VERSION 5.8 ;
BUSBITCHARS "[]" ;
DIVIDERCHAR "/" ;
UNITS
    DATABASE MICRONS 2000 ;
END UNITS

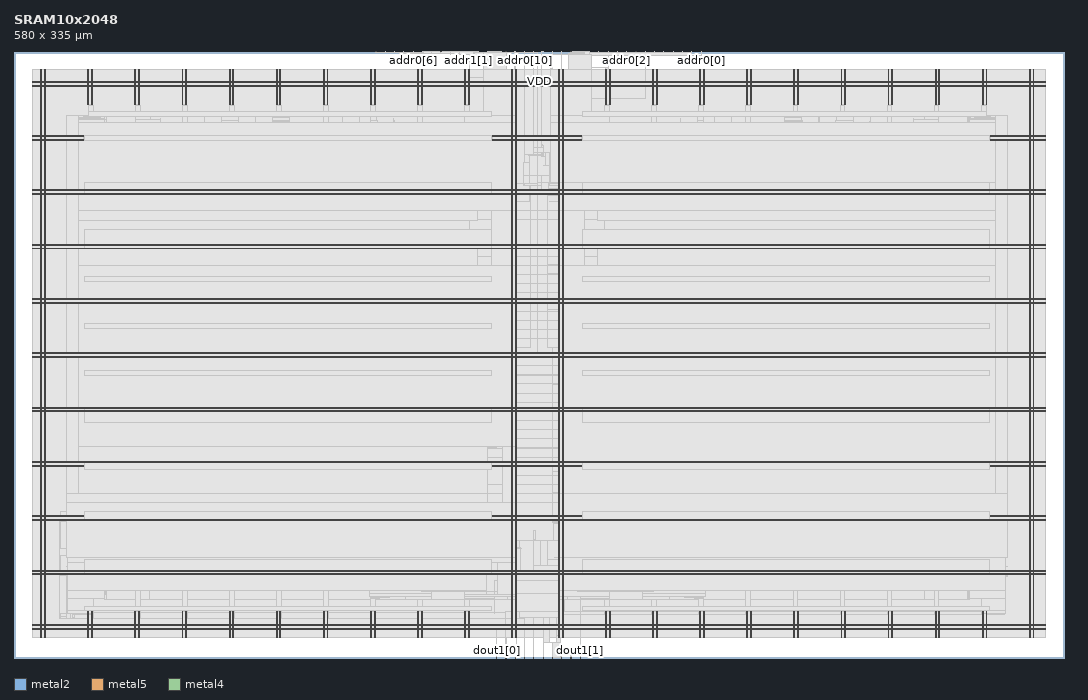
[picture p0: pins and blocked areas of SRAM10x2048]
MACRO SRAM10x2048
  FOREIGN SRAM10x2048 0 0 ;
  CLASS BLOCK ;
  SIZE 580 BY 335 ;
  PIN addr0[0]
    DIRECTION INPUT ;
    USE SIGNAL ;
    PORT
      LAYER metal2 ;
        RECT  379.49 334.93 379.56 335 ;
    END
  END addr0[0]
  PIN addr0[10]
    DIRECTION INPUT ;
    USE SIGNAL ;
    PORT
      LAYER metal2 ;
        RECT  282.02 334.93 282.09 335 ;
    END
  END addr0[10]
  PIN addr0[1]
    DIRECTION INPUT ;
    USE SIGNAL ;
    PORT
      LAYER metal2 ;
        RECT  369.23 334.93 369.3 335 ;
    END
  END addr0[1]
  PIN addr0[2]
    DIRECTION INPUT ;
    USE SIGNAL ;
    PORT
      LAYER metal2 ;
        RECT  338.45 334.93 338.52 335 ;
    END
  END addr0[2]
  PIN addr0[3]
    DIRECTION INPUT ;
    USE SIGNAL ;
    PORT
      LAYER metal2 ;
        RECT  374.36 334.93 374.43 335 ;
    END
  END addr0[3]
  PIN addr0[4]
    DIRECTION INPUT ;
    USE SIGNAL ;
    PORT
      LAYER metal2 ;
        RECT  240.98 334.93 241.05 335 ;
    END
  END addr0[4]
  PIN addr0[5]
    DIRECTION INPUT ;
    USE SIGNAL ;
    PORT
      LAYER metal2 ;
        RECT  302.54 334.93 302.61 335 ;
    END
  END addr0[5]
  PIN addr0[6]
    DIRECTION INPUT ;
    USE SIGNAL ;
    PORT
      LAYER metal2 ;
        RECT  220.46 334.93 220.53 335 ;
    END
  END addr0[6]
  PIN addr0[7]
    DIRECTION INPUT ;
    USE SIGNAL ;
    PORT
      LAYER metal2 ;
        RECT  261.5 334.93 261.57 335 ;
    END
  END addr0[7]
  PIN addr0[8]
    DIRECTION INPUT ;
    USE SIGNAL ;
    PORT
      LAYER metal2 ;
        RECT  317.93 334.93 318 335 ;
    END
  END addr0[8]
  PIN addr0[9]
    DIRECTION INPUT ;
    USE SIGNAL ;
    PORT
      LAYER metal2 ;
        RECT  235.85 334.93 235.92 335 ;
    END
  END addr0[9]
  PIN addr1[0]
    DIRECTION INPUT ;
    USE SIGNAL ;
    PORT
      LAYER metal2 ;
        RECT  328.19 334.93 328.26 335 ;
    END
  END addr1[0]
  PIN addr1[10]
    DIRECTION INPUT ;
    USE SIGNAL ;
    PORT
      LAYER metal2 ;
        RECT  292.28 334.93 292.35 335 ;
    END
  END addr1[10]
  PIN addr1[1]
    DIRECTION INPUT ;
    USE SIGNAL ;
    PORT
      LAYER metal2 ;
        RECT  251.24 334.93 251.31 335 ;
    END
  END addr1[1]
  PIN addr1[2]
    DIRECTION INPUT ;
    USE SIGNAL ;
    PORT
      LAYER metal2 ;
        RECT  271.76 334.93 271.83 335 ;
    END
  END addr1[2]
  PIN addr1[3]
    DIRECTION INPUT ;
    USE SIGNAL ;
    PORT
      LAYER metal2 ;
        RECT  333.32 334.93 333.39 335 ;
    END
  END addr1[3]
  PIN addr1[4]
    DIRECTION INPUT ;
    USE SIGNAL ;
    PORT
      LAYER metal2 ;
        RECT  230.72 334.93 230.79 335 ;
    END
  END addr1[4]
  PIN addr1[5]
    DIRECTION INPUT ;
    USE SIGNAL ;
    PORT
      LAYER metal2 ;
        RECT  256.37 334.93 256.44 335 ;
    END
  END addr1[5]
  PIN addr1[6]
    DIRECTION INPUT ;
    USE SIGNAL ;
    PORT
      LAYER metal2 ;
        RECT  266.63 334.93 266.7 335 ;
    END
  END addr1[6]
  PIN addr1[7]
    DIRECTION INPUT ;
    USE SIGNAL ;
    PORT
      LAYER metal2 ;
        RECT  348.71 334.93 348.78 335 ;
    END
  END addr1[7]
  PIN addr1[8]
    DIRECTION INPUT ;
    USE SIGNAL ;
    PORT
      LAYER metal2 ;
        RECT  323.06 334.93 323.13 335 ;
    END
  END addr1[8]
  PIN addr1[9]
    DIRECTION INPUT ;
    USE SIGNAL ;
    PORT
      LAYER metal2 ;
        RECT  210.2 334.93 210.27 335 ;
    END
  END addr1[9]
  PIN clk0
    DIRECTION INPUT ;
    USE SIGNAL ;
    PORT
      LAYER metal2 ;
        RECT  225.59 334.93 225.66 335 ;
    END
  END clk0
  PIN clk1
    DIRECTION INPUT ;
    USE SIGNAL ;
    PORT
      LAYER metal2 ;
        RECT  358.97 334.93 359.04 335 ;
    END
  END clk1
  PIN csb0
    DIRECTION INPUT ;
    USE SIGNAL ;
    PORT
      LAYER metal2 ;
        RECT  297.41 334.93 297.48 335 ;
    END
  END csb0
  PIN csb1
    DIRECTION INPUT ;
    USE SIGNAL ;
    PORT
      LAYER metal2 ;
        RECT  287.15 334.93 287.22 335 ;
    END
  END csb1
  PIN din0[0]
    DIRECTION INPUT ;
    USE SIGNAL ;
    PORT
      LAYER metal2 ;
        RECT  205.07 334.93 205.14 335 ;
    END
  END din0[0]
  PIN din0[1]
    DIRECTION INPUT ;
    USE SIGNAL ;
    PORT
      LAYER metal2 ;
        RECT  215.33 334.93 215.4 335 ;
    END
  END din0[1]
  PIN din0[2]
    DIRECTION INPUT ;
    USE SIGNAL ;
    PORT
      LAYER metal2 ;
        RECT  312.8 334.93 312.87 335 ;
    END
  END din0[2]
  PIN din0[3]
    DIRECTION INPUT ;
    USE SIGNAL ;
    PORT
      LAYER metal2 ;
        RECT  343.58 334.93 343.65 335 ;
    END
  END din0[3]
  PIN din0[4]
    DIRECTION INPUT ;
    USE SIGNAL ;
    PORT
      LAYER metal2 ;
        RECT  276.89 334.93 276.96 335 ;
    END
  END din0[4]
  PIN din0[5]
    DIRECTION INPUT ;
    USE SIGNAL ;
    PORT
      LAYER metal2 ;
        RECT  199.94 334.93 200.01 335 ;
    END
  END din0[5]
  PIN din0[6]
    DIRECTION INPUT ;
    USE SIGNAL ;
    PORT
      LAYER metal2 ;
        RECT  364.1 334.93 364.17 335 ;
    END
  END din0[6]
  PIN din0[7]
    DIRECTION INPUT ;
    USE SIGNAL ;
    PORT
      LAYER metal2 ;
        RECT  307.67 334.93 307.74 335 ;
    END
  END din0[7]
  PIN din0[8]
    DIRECTION INPUT ;
    USE SIGNAL ;
    PORT
      LAYER metal2 ;
        RECT  353.84 334.93 353.91 335 ;
    END
  END din0[8]
  PIN din0[9]
    DIRECTION INPUT ;
    USE SIGNAL ;
    PORT
      LAYER metal2 ;
        RECT  246.11 334.93 246.18 335 ;
    END
  END din0[9]
  PIN dout1[0]
    DIRECTION OUTPUT ;
    USE SIGNAL ;
    PORT
      LAYER metal2 ;
        RECT  266.63 0 266.7 0.07 ;
    END
  END dout1[0]
  PIN dout1[1]
    DIRECTION OUTPUT ;
    USE SIGNAL ;
    PORT
      LAYER metal2 ;
        RECT  312.8 0 312.87 0.07 ;
    END
  END dout1[1]
  PIN dout1[2]
    DIRECTION OUTPUT ;
    USE SIGNAL ;
    PORT
      LAYER metal2 ;
        RECT  287.15 0 287.22 0.07 ;
    END
  END dout1[2]
  PIN dout1[3]
    DIRECTION OUTPUT ;
    USE SIGNAL ;
    PORT
      LAYER metal2 ;
        RECT  297.41 0 297.48 0.07 ;
    END
  END dout1[3]
  PIN dout1[4]
    DIRECTION OUTPUT ;
    USE SIGNAL ;
    PORT
      LAYER metal2 ;
        RECT  276.89 0 276.96 0.07 ;
    END
  END dout1[4]
  PIN dout1[5]
    DIRECTION OUTPUT ;
    USE SIGNAL ;
    PORT
      LAYER metal2 ;
        RECT  307.67 0 307.74 0.07 ;
    END
  END dout1[5]
  PIN dout1[6]
    DIRECTION OUTPUT ;
    USE SIGNAL ;
    PORT
      LAYER metal2 ;
        RECT  292.28 0 292.35 0.07 ;
    END
  END dout1[6]
  PIN dout1[7]
    DIRECTION OUTPUT ;
    USE SIGNAL ;
    PORT
      LAYER metal2 ;
        RECT  282.02 0 282.09 0.07 ;
    END
  END dout1[7]
  PIN dout1[8]
    DIRECTION OUTPUT ;
    USE SIGNAL ;
    PORT
      LAYER metal2 ;
        RECT  271.76 0 271.83 0.07 ;
    END
  END dout1[8]
  PIN dout1[9]
    DIRECTION OUTPUT ;
    USE SIGNAL ;
    PORT
      LAYER metal2 ;
        RECT  302.54 0 302.61 0.07 ;
    END
  END dout1[9]
  PIN VSS
    DIRECTION INOUT ;
    USE GROUND ;
    PORT
      LAYER metal5 ;
        RECT  539.38 285.95 570 286.45 ;
        RECT  539.38 105.95 570 106.45 ;
        RECT  264.47 285.95 313.53 286.45 ;
        RECT  264.47 105.95 313.53 106.45 ;
        RECT  10.07 315.95 570 316.45 ;
        RECT  10.07 285.95 38.62 286.45 ;
        RECT  10.07 255.95 570 256.45 ;
        RECT  10.07 225.95 570 226.45 ;
        RECT  10.07 195.95 570 196.45 ;
        RECT  10.07 165.95 570 166.45 ;
        RECT  10.07 135.95 570 136.45 ;
        RECT  10.07 105.95 38.62 106.45 ;
        RECT  10.07 75.95 570 76.45 ;
        RECT  10.07 45.95 570 46.45 ;
        RECT  10.07 15.95 570 16.45 ;
      LAYER metal4 ;
        RECT  560.82 11.13 561.32 324.87 ;
        RECT  534.82 305.5 535.32 324.87 ;
        RECT  534.82 11.13 535.32 25.53 ;
        RECT  508.82 305.5 509.32 324.87 ;
        RECT  508.82 11.13 509.32 25.53 ;
        RECT  482.82 305.5 483.32 324.87 ;
        RECT  482.82 11.13 483.32 25.53 ;
        RECT  456.82 305.5 457.32 324.87 ;
        RECT  456.82 11.13 457.32 25.53 ;
        RECT  430.82 305.5 431.32 324.87 ;
        RECT  430.82 11.13 431.32 25.53 ;
        RECT  404.82 305.5 405.32 324.87 ;
        RECT  404.82 11.13 405.32 25.53 ;
        RECT  378.82 305.5 379.32 324.87 ;
        RECT  378.82 11.13 379.32 25.53 ;
        RECT  352.82 305.5 353.32 324.87 ;
        RECT  352.82 11.13 353.32 25.53 ;
        RECT  326.82 305.5 327.32 324.87 ;
        RECT  326.82 11.13 327.32 25.53 ;
        RECT  300.82 11.13 301.32 324.87 ;
        RECT  274.82 11.13 275.32 324.87 ;
        RECT  248.82 305.53 249.32 324.87 ;
        RECT  248.82 11.13 249.32 25.74 ;
        RECT  222.82 305.53 223.32 324.87 ;
        RECT  222.82 11.13 223.32 25.74 ;
        RECT  196.82 305.53 197.32 324.87 ;
        RECT  196.82 11.13 197.32 25.74 ;
        RECT  170.82 305.53 171.32 324.87 ;
        RECT  170.82 11.13 171.32 25.74 ;
        RECT  144.82 305.53 145.32 324.87 ;
        RECT  144.82 11.13 145.32 25.74 ;
        RECT  118.82 305.53 119.32 324.87 ;
        RECT  118.82 11.13 119.32 25.74 ;
        RECT  92.82 305.53 93.32 324.87 ;
        RECT  92.82 11.13 93.32 25.74 ;
        RECT  66.82 305.53 67.32 324.87 ;
        RECT  66.82 11.13 67.32 25.74 ;
        RECT  40.82 305.53 41.32 324.87 ;
        RECT  40.82 11.13 41.32 25.74 ;
        RECT  14.82 11.13 15.32 324.87 ;
    END
  END VSS
  PIN VDD
    DIRECTION INOUT ;
    USE POWER ;
    PORT
      LAYER metal5 ;
        RECT  539.38 288.05 570 288.55 ;
        RECT  539.38 78.05 570 78.55 ;
        RECT  264.47 288.05 313.53 288.55 ;
        RECT  264.47 78.05 313.53 78.55 ;
        RECT  10.07 318.05 570 318.55 ;
        RECT  10.07 288.05 38.62 288.55 ;
        RECT  10.07 258.05 570 258.55 ;
        RECT  10.07 228.05 570 228.55 ;
        RECT  10.07 198.05 570 198.55 ;
        RECT  10.07 168.05 570 168.55 ;
        RECT  10.07 138.05 570 138.55 ;
        RECT  10.07 108.05 570 108.55 ;
        RECT  10.07 78.05 38.62 78.55 ;
        RECT  10.07 48.05 570 48.55 ;
        RECT  10.07 18.05 570 18.55 ;
      LAYER metal4 ;
        RECT  562.92 11.16 563.42 324.84 ;
        RECT  536.92 305.53 537.42 324.84 ;
        RECT  536.92 11.16 537.42 25.74 ;
        RECT  510.92 305.53 511.42 324.84 ;
        RECT  510.92 11.16 511.42 25.74 ;
        RECT  484.92 305.53 485.42 324.84 ;
        RECT  484.92 11.16 485.42 25.74 ;
        RECT  458.92 305.53 459.42 324.84 ;
        RECT  458.92 11.16 459.42 25.74 ;
        RECT  432.92 305.53 433.42 324.84 ;
        RECT  432.92 11.16 433.42 25.74 ;
        RECT  406.92 305.53 407.42 324.84 ;
        RECT  406.92 11.16 407.42 25.74 ;
        RECT  380.92 305.53 381.42 324.84 ;
        RECT  380.92 11.16 381.42 25.74 ;
        RECT  354.92 305.53 355.42 324.84 ;
        RECT  354.92 11.16 355.42 25.74 ;
        RECT  328.92 305.53 329.42 324.84 ;
        RECT  328.92 11.16 329.42 25.74 ;
        RECT  302.92 11.16 303.42 324.84 ;
        RECT  276.92 11.16 277.42 324.84 ;
        RECT  250.92 305.5 251.42 324.84 ;
        RECT  250.92 11.16 251.42 25.53 ;
        RECT  224.92 305.5 225.42 324.84 ;
        RECT  224.92 11.16 225.42 25.53 ;
        RECT  198.92 305.5 199.42 324.84 ;
        RECT  198.92 11.16 199.42 25.53 ;
        RECT  172.92 305.5 173.42 324.84 ;
        RECT  172.92 11.16 173.42 25.53 ;
        RECT  146.92 305.5 147.42 324.84 ;
        RECT  146.92 11.16 147.42 25.53 ;
        RECT  120.92 305.5 121.42 324.84 ;
        RECT  120.92 11.16 121.42 25.53 ;
        RECT  94.92 305.5 95.42 324.84 ;
        RECT  94.92 11.16 95.42 25.53 ;
        RECT  68.92 305.5 69.42 324.84 ;
        RECT  68.92 11.16 69.42 25.53 ;
        RECT  42.92 305.5 43.42 324.84 ;
        RECT  42.92 11.16 43.42 25.53 ;
        RECT  16.92 11.16 17.42 324.84 ;
    END
  END VDD
  OBS
    LAYER metal1 ;
     RECT  10.07 11.115 570 324.885 ;
    LAYER metal2 ;
     RECT  277.08 0 277.72 0.035 ;
     RECT  297.41 0.035 297.48 0.14 ;
     RECT  302.54 0.035 302.61 0.14 ;
     RECT  276.89 0.035 277.72 0.245 ;
     RECT  297.41 0.14 302.61 0.28 ;
     RECT  312.8 0.035 312.87 0.28 ;
     RECT  307.67 0.035 307.74 2.94 ;
     RECT  292.28 0.035 292.35 8.54 ;
     RECT  297.41 0.28 302.04 8.54 ;
     RECT  292.28 8.54 302.04 8.68 ;
     RECT  271.76 0.035 271.83 11.13 ;
     RECT  277.65 0.245 277.72 11.13 ;
     RECT  14.84 11.13 15.3 12.53 ;
     RECT  40.84 11.13 41.3 12.53 ;
     RECT  66.84 11.13 67.3 12.53 ;
     RECT  92.84 11.13 93.3 12.53 ;
     RECT  118.84 11.13 119.3 12.53 ;
     RECT  144.84 11.13 145.3 12.53 ;
     RECT  170.84 11.13 171.3 12.53 ;
     RECT  196.84 11.13 197.3 12.53 ;
     RECT  222.84 11.13 223.3 12.53 ;
     RECT  248.84 11.13 249.3 12.53 ;
     RECT  299.88 8.68 302.04 12.53 ;
     RECT  326.84 11.13 327.3 12.53 ;
     RECT  352.84 11.13 353.3 12.53 ;
     RECT  378.84 11.13 379.3 12.53 ;
     RECT  404.84 11.13 405.3 12.53 ;
     RECT  430.84 11.13 431.3 12.53 ;
     RECT  456.84 11.13 457.3 12.53 ;
     RECT  482.84 11.13 483.3 12.53 ;
     RECT  508.84 11.13 509.3 12.53 ;
     RECT  534.84 11.13 535.3 12.53 ;
     RECT  560.84 11.13 561.3 12.53 ;
     RECT  266.63 0.035 266.7 17.22 ;
     RECT  271.76 11.13 277.72 21.98 ;
     RECT  282.02 0.035 282.09 21.98 ;
     RECT  292.28 8.68 295.96 22.12 ;
     RECT  299.88 12.53 303.4 22.12 ;
     RECT  25.33 21.98 25.4 22.68 ;
     RECT  326.84 12.53 329.4 23.87 ;
     RECT  352.84 12.53 355.4 23.87 ;
     RECT  378.84 12.53 381.4 23.87 ;
     RECT  404.84 12.53 407.4 23.87 ;
     RECT  430.84 12.53 433.4 23.87 ;
     RECT  456.84 12.53 459.4 23.87 ;
     RECT  482.84 12.53 485.4 23.87 ;
     RECT  508.84 12.53 511.4 23.87 ;
     RECT  534.84 12.53 537.4 23.87 ;
     RECT  287.15 0.035 287.22 24.22 ;
     RECT  292.28 22.12 303.4 24.22 ;
     RECT  287.15 24.22 303.94 24.36 ;
     RECT  287.15 24.36 304.32 24.64 ;
     RECT  25.33 22.68 25.59 24.78 ;
     RECT  271.76 21.98 282.09 24.92 ;
     RECT  286.96 24.64 304.32 24.92 ;
     RECT  40.84 12.53 43.4 25.27 ;
     RECT  66.84 12.53 69.4 25.27 ;
     RECT  92.84 12.53 95.4 25.27 ;
     RECT  118.84 12.53 121.4 25.27 ;
     RECT  144.84 12.53 147.4 25.27 ;
     RECT  170.84 12.53 173.4 25.27 ;
     RECT  196.84 12.53 199.4 25.27 ;
     RECT  222.84 12.53 225.4 25.27 ;
     RECT  248.84 12.53 251.4 25.27 ;
     RECT  271.76 24.92 304.32 25.76 ;
     RECT  41.1 25.27 43.4 26.25 ;
     RECT  67.1 25.27 69.4 26.25 ;
     RECT  93.1 25.27 95.4 26.25 ;
     RECT  119.1 25.27 121.4 26.25 ;
     RECT  145.1 25.27 147.4 26.25 ;
     RECT  171.1 25.27 173.4 26.25 ;
     RECT  197.1 25.27 199.4 26.25 ;
     RECT  223.1 25.27 225.4 26.25 ;
     RECT  249.1 25.27 251.4 26.25 ;
     RECT  326.84 23.87 328.9 26.25 ;
     RECT  352.84 23.87 354.9 26.25 ;
     RECT  378.84 23.87 380.9 26.25 ;
     RECT  404.84 23.87 406.9 26.25 ;
     RECT  430.84 23.87 432.9 26.25 ;
     RECT  456.84 23.87 458.9 26.25 ;
     RECT  482.84 23.87 484.9 26.25 ;
     RECT  508.84 23.87 510.9 26.25 ;
     RECT  534.84 23.87 536.9 26.25 ;
     RECT  50.81 33.04 50.88 34.44 ;
     RECT  527.12 33.04 527.19 34.44 ;
     RECT  239.67 34.58 239.74 34.72 ;
     RECT  338.26 34.58 338.33 34.72 ;
     RECT  239.48 34.72 239.74 34.755 ;
     RECT  338.26 34.72 338.52 34.755 ;
     RECT  274.61 25.76 304.32 35.7 ;
     RECT  50.62 34.44 50.88 37.32 ;
     RECT  67.1 26.25 69.66 37.32 ;
     RECT  93.1 26.25 95.66 37.32 ;
     RECT  119.1 26.25 121.66 37.32 ;
     RECT  145.1 26.25 147.66 37.32 ;
     RECT  171.1 26.25 173.66 37.32 ;
     RECT  197.1 26.25 199.66 37.32 ;
     RECT  223.1 26.25 225.66 37.32 ;
     RECT  239.29 34.755 239.74 37.32 ;
     RECT  249.1 26.25 251.66 37.32 ;
     RECT  326.34 26.25 328.9 37.32 ;
     RECT  338.26 34.755 338.71 37.32 ;
     RECT  352.34 26.25 354.9 37.32 ;
     RECT  378.34 26.25 380.9 37.32 ;
     RECT  404.34 26.25 406.9 37.32 ;
     RECT  430.34 26.25 432.9 37.32 ;
     RECT  456.34 26.25 458.9 37.32 ;
     RECT  482.34 26.25 484.9 37.32 ;
     RECT  508.34 26.25 510.9 37.32 ;
     RECT  527.12 34.44 527.38 37.32 ;
     RECT  274.42 35.7 304.32 42.665 ;
     RECT  265.3 35 265.37 42.7 ;
     RECT  25.33 24.78 29.2 45.36 ;
     RECT  547.26 24.64 547.33 45.36 ;
     RECT  274.61 42.665 304.32 46.9 ;
     RECT  274.84 46.9 304.32 47.04 ;
     RECT  286.96 47.04 304.32 51.1 ;
     RECT  294.94 51.1 304.32 54.18 ;
     RECT  50.62 37.32 251.705 55.93 ;
     RECT  326.295 37.32 527.38 55.93 ;
     RECT  25.33 45.36 25.59 56.84 ;
     RECT  50.81 55.93 251.705 57.96 ;
     RECT  326.295 55.93 527.19 57.96 ;
     RECT  274.84 47.04 279.81 60.34 ;
     RECT  25.33 56.84 29.2 60.48 ;
     RECT  274.84 60.34 280.19 60.48 ;
     RECT  274.84 60.48 279.81 61.04 ;
     RECT  286.96 51.1 290.83 64.96 ;
     RECT  294.94 54.18 304.13 64.96 ;
     RECT  274.84 61.04 279.05 65.1 ;
     RECT  286.77 64.96 290.83 65.1 ;
     RECT  294.75 64.96 304.13 65.1 ;
     RECT  286.77 65.1 287.98 70.28 ;
     RECT  286.77 70.28 287.6 70.7 ;
     RECT  297.98 65.1 304.13 74.135 ;
     RECT  297.98 74.135 303.94 75.005 ;
     RECT  297.98 75.005 303.4 75.04 ;
     RECT  25.33 60.48 25.59 75.74 ;
     RECT  25.52 75.74 25.59 80.78 ;
     RECT  297.6 75.04 303.4 85.82 ;
     RECT  274.84 65.1 277.4 91 ;
     RECT  297.6 85.82 304.13 91.28 ;
     RECT  297.6 91.28 303.4 100.94 ;
     RECT  297.6 100.94 304.13 102.76 ;
     RECT  274.04 91 277.4 106.68 ;
     RECT  273.85 106.68 277.4 111.02 ;
     RECT  273.66 111.02 277.4 117.18 ;
     RECT  274.04 117.18 277.4 121.8 ;
     RECT  273.66 121.8 277.4 122.64 ;
     RECT  273.85 122.64 277.4 136.92 ;
     RECT  274.04 136.92 277.4 141.96 ;
     RECT  297.6 102.76 303.4 151.34 ;
     RECT  297.6 151.34 305.08 161.7 ;
     RECT  297.6 161.7 303.4 166.88 ;
     RECT  282.4 166.32 282.47 167.02 ;
     RECT  296.84 166.88 303.4 167.02 ;
     RECT  289.43 167.02 289.5 167.16 ;
     RECT  282.02 167.02 282.09 167.44 ;
     RECT  289.05 167.3 289.12 167.44 ;
     RECT  296.08 167.02 303.4 167.44 ;
     RECT  297.6 167.44 303.4 171.36 ;
     RECT  294.94 171.36 303.4 186.48 ;
     RECT  294.94 186.48 303.56 192.36 ;
     RECT  294.94 192.36 304.13 196.98 ;
     RECT  294.94 196.98 303.56 212.52 ;
     RECT  294.94 212.52 304.13 217.42 ;
     RECT  285.44 171.36 285.51 252.14 ;
     RECT  294.94 217.42 304.32 255.36 ;
     RECT  294.56 255.36 304.32 259.42 ;
     RECT  291.33 259.42 304.32 259.56 ;
     RECT  284.68 252.14 285.51 260.68 ;
     RECT  284.68 260.68 285.13 260.96 ;
     RECT  281.64 260.96 285.13 261.1 ;
     RECT  291.33 259.56 303.4 261.1 ;
     RECT  273.66 141.96 277.4 261.66 ;
     RECT  262.07 261.66 262.14 261.94 ;
     RECT  273.85 261.66 277.4 261.94 ;
     RECT  291.33 261.1 291.4 262.22 ;
     RECT  289.43 262.22 291.4 262.5 ;
     RECT  289.05 262.5 291.4 262.64 ;
     RECT  291.33 262.64 291.4 266.28 ;
     RECT  281.64 261.1 284.94 266.7 ;
     RECT  291.14 266.56 291.21 266.7 ;
     RECT  295.7 261.1 303.4 272.16 ;
     RECT  292.66 272.16 303.4 272.3 ;
     RECT  281.64 266.7 284.75 273.565 ;
     RECT  281.64 273.565 284.94 273.635 ;
     RECT  293.42 272.3 303.4 276.92 ;
     RECT  282.02 273.635 284.94 277.9 ;
     RECT  282.02 277.9 287.22 278.04 ;
     RECT  287.15 278.04 287.22 279.3 ;
     RECT  291.14 276.92 303.4 279.3 ;
     RECT  287.15 279.3 292.35 282.1 ;
     RECT  291.14 282.1 292.35 283.08 ;
     RECT  291.14 283.08 292.16 283.5 ;
     RECT  51.04 57.96 251.705 295.53 ;
     RECT  326.295 57.96 526.96 295.53 ;
     RECT  316.41 259.42 316.48 298.06 ;
     RECT  261.88 261.94 262.14 299.18 ;
     RECT  261.88 299.18 261.95 299.32 ;
     RECT  41.1 26.25 43.66 303.59 ;
     RECT  67.1 295.53 69.66 303.59 ;
     RECT  93.1 295.53 95.66 303.59 ;
     RECT  119.1 295.53 121.66 303.59 ;
     RECT  145.1 295.53 147.66 303.59 ;
     RECT  171.1 295.53 173.66 303.59 ;
     RECT  197.1 295.53 199.66 303.59 ;
     RECT  223.1 295.53 225.66 303.59 ;
     RECT  249.1 295.53 251.66 303.59 ;
     RECT  326.34 295.53 328.9 303.59 ;
     RECT  352.34 295.53 354.9 303.59 ;
     RECT  378.34 295.53 380.9 303.59 ;
     RECT  404.34 295.53 406.9 303.59 ;
     RECT  430.34 295.53 432.9 303.59 ;
     RECT  456.34 295.53 458.9 303.59 ;
     RECT  482.34 295.53 484.9 303.59 ;
     RECT  508.34 295.53 510.9 303.59 ;
     RECT  534.34 26.25 536.9 303.59 ;
     RECT  328.44 303.59 328.9 306.53 ;
     RECT  354.44 303.59 354.9 306.53 ;
     RECT  380.44 303.59 380.9 306.53 ;
     RECT  406.44 303.59 406.9 306.53 ;
     RECT  432.44 303.59 432.9 306.53 ;
     RECT  458.44 303.59 458.9 306.53 ;
     RECT  484.44 303.59 484.9 306.53 ;
     RECT  510.44 303.59 510.9 306.53 ;
     RECT  536.44 303.59 536.9 306.53 ;
     RECT  41.1 303.59 43.4 307.93 ;
     RECT  67.1 303.59 69.4 307.93 ;
     RECT  93.1 303.59 95.4 307.93 ;
     RECT  119.1 303.59 121.4 307.93 ;
     RECT  145.1 303.59 147.4 307.93 ;
     RECT  171.1 303.59 173.4 307.93 ;
     RECT  197.1 303.59 199.4 307.93 ;
     RECT  223.1 303.59 225.4 307.93 ;
     RECT  249.1 303.59 251.4 307.93 ;
     RECT  328.44 306.53 329.4 307.93 ;
     RECT  354.44 306.53 355.4 307.93 ;
     RECT  380.44 306.53 381.4 307.93 ;
     RECT  406.44 306.53 407.4 307.93 ;
     RECT  432.44 306.53 433.4 307.93 ;
     RECT  458.44 306.53 459.4 307.93 ;
     RECT  484.44 306.53 485.4 307.93 ;
     RECT  510.44 306.53 511.4 307.93 ;
     RECT  536.44 306.53 537.4 307.93 ;
     RECT  274.84 261.94 277.4 310.52 ;
     RECT  297.79 279.3 303.4 313.465 ;
     RECT  248.84 307.93 251.4 320.74 ;
     RECT  14.84 12.53 17.4 323.47 ;
     RECT  40.84 307.93 43.4 323.47 ;
     RECT  66.84 307.93 69.4 323.47 ;
     RECT  92.84 307.93 95.4 323.47 ;
     RECT  118.84 307.93 121.4 323.47 ;
     RECT  144.84 307.93 147.4 323.47 ;
     RECT  170.84 307.93 173.4 323.47 ;
     RECT  196.84 307.93 199.4 323.47 ;
     RECT  222.84 307.93 225.4 323.47 ;
     RECT  271.76 310.52 277.4 323.47 ;
     RECT  297.41 313.465 303.4 323.47 ;
     RECT  326.84 307.93 329.4 323.47 ;
     RECT  352.84 307.93 355.4 323.47 ;
     RECT  378.84 307.93 381.4 323.47 ;
     RECT  404.84 307.93 407.4 323.47 ;
     RECT  430.84 307.93 433.4 323.47 ;
     RECT  456.84 307.93 459.4 323.47 ;
     RECT  482.84 307.93 485.4 323.47 ;
     RECT  508.84 307.93 511.4 323.47 ;
     RECT  534.84 307.93 537.4 323.47 ;
     RECT  560.84 12.53 563.4 323.47 ;
     RECT  14.84 323.47 15.3 324.87 ;
     RECT  40.84 323.47 41.3 324.87 ;
     RECT  66.84 323.47 67.3 324.87 ;
     RECT  92.84 323.47 93.3 324.87 ;
     RECT  118.84 323.47 119.3 324.87 ;
     RECT  144.84 323.47 145.3 324.87 ;
     RECT  170.84 323.47 171.3 324.87 ;
     RECT  196.84 323.47 197.3 324.87 ;
     RECT  222.84 323.47 223.3 324.87 ;
     RECT  248.84 320.74 251.69 324.87 ;
     RECT  271.76 323.47 276.77 324.87 ;
     RECT  297.41 323.47 302.61 324.87 ;
     RECT  326.84 323.47 328.26 324.87 ;
     RECT  352.84 323.47 353.3 324.87 ;
     RECT  378.84 323.47 379.3 324.87 ;
     RECT  404.84 323.47 405.3 324.87 ;
     RECT  430.84 323.47 431.3 324.87 ;
     RECT  456.84 323.47 457.3 324.87 ;
     RECT  482.84 323.47 483.3 324.87 ;
     RECT  508.84 323.47 509.3 324.87 ;
     RECT  534.84 323.47 535.3 324.87 ;
     RECT  560.84 323.47 561.3 324.87 ;
     RECT  251.62 324.87 251.69 332.78 ;
     RECT  251.62 332.78 253.78 333.34 ;
     RECT  323.82 333.48 323.89 333.9 ;
     RECT  323.44 333.9 323.89 334.04 ;
     RECT  323.44 334.04 323.51 334.32 ;
     RECT  323.06 334.32 323.51 334.46 ;
     RECT  251.62 333.34 254.16 334.6 ;
     RECT  225.02 334.495 226.42 334.74 ;
     RECT  251.62 334.6 256.44 334.775 ;
     RECT  276.7 324.87 276.77 334.775 ;
     RECT  291.14 283.5 291.21 334.775 ;
     RECT  276.7 334.775 276.96 334.845 ;
     RECT  225.59 334.74 226.04 334.88 ;
     RECT  251.24 334.775 256.44 334.88 ;
     RECT  199.94 334.6 200.01 334.965 ;
     RECT  205.07 334.46 205.14 334.965 ;
     RECT  210.2 334.32 210.27 334.965 ;
     RECT  215.33 334.04 215.4 334.965 ;
     RECT  220.46 334.18 220.53 334.965 ;
     RECT  225.59 334.88 225.66 334.965 ;
     RECT  230.72 333.9 230.79 334.965 ;
     RECT  235.85 333.76 235.92 334.965 ;
     RECT  240.98 333.62 241.05 334.965 ;
     RECT  246.11 333.48 246.18 334.965 ;
     RECT  251.24 334.88 251.69 334.965 ;
     RECT  256.37 334.88 256.44 334.965 ;
     RECT  261.5 334.74 261.57 334.965 ;
     RECT  266.63 334.74 266.7 334.965 ;
     RECT  271.76 324.87 271.83 334.965 ;
     RECT  276.89 334.845 276.96 334.965 ;
     RECT  282.02 278.04 282.09 334.965 ;
     RECT  287.15 282.1 287.22 334.965 ;
     RECT  291.14 334.775 292.35 334.965 ;
     RECT  297.41 324.87 297.48 334.965 ;
     RECT  302.54 324.87 302.61 334.965 ;
     RECT  307.67 334.74 307.74 334.965 ;
     RECT  312.8 334.46 312.87 334.965 ;
     RECT  317.93 334.74 318 334.965 ;
     RECT  323.06 334.46 323.13 334.965 ;
     RECT  328.19 324.87 328.26 334.965 ;
     RECT  333.32 333.62 333.39 334.965 ;
     RECT  338.45 333.76 338.52 334.965 ;
     RECT  343.58 334.04 343.65 334.965 ;
     RECT  348.71 309.12 348.78 334.965 ;
     RECT  353.84 333.9 353.91 334.965 ;
     RECT  358.97 333.2 359.04 334.965 ;
     RECT  364.1 334.32 364.17 334.965 ;
     RECT  369.23 334.18 369.3 334.965 ;
     RECT  374.36 334.46 374.43 334.965 ;
     RECT  379.49 332.92 379.56 334.965 ;
     RECT  251.43 334.965 251.69 335 ;
     RECT  291.14 334.965 292.16 335 ;
    LAYER metal3 ;
     RECT  14.84 11.13 15.3 324.87 ;
     RECT  15.3 12.53 17.4 323.47 ;
     RECT  25.295 22.015 25.485 22.085 ;
     RECT  25.485 22.015 29.095 22.785 ;
     RECT  29 55.335 29.095 55.545 ;
     RECT  29 45.255 29.235 45.465 ;
     RECT  29 60.375 29.235 60.585 ;
     RECT  29.095 55.335 29.565 56.945 ;
     RECT  29.095 22.015 31.105 24.885 ;
     RECT  29.565 56.875 31.245 56.945 ;
     RECT  29 90.615 32.645 90.825 ;
     RECT  29 85.575 32.925 85.785 ;
     RECT  29 70.455 33.205 70.665 ;
     RECT  29 50.295 33.485 50.505 ;
     RECT  29.115 299.495 35.835 299.565 ;
     RECT  32.925 85.715 35.975 85.785 ;
     RECT  29 65.555 36.705 65.765 ;
     RECT  36.705 65.275 36.81 65.765 ;
     RECT  36.81 65.275 36.845 65.345 ;
     RECT  35.835 298.235 38.635 299.565 ;
     RECT  31.105 22.015 40.84 25.025 ;
     RECT  40.84 11.13 41.1 25.27 ;
     RECT  29.235 45.395 41.1 45.465 ;
     RECT  33.485 50.435 41.1 50.505 ;
     RECT  29.235 60.515 41.1 60.585 ;
     RECT  33.205 70.595 41.1 70.665 ;
     RECT  25.295 75.635 41.1 75.705 ;
     RECT  25.485 80.675 41.1 80.745 ;
     RECT  32.645 90.755 41.1 90.825 ;
     RECT  38.635 298.235 41.1 299.705 ;
     RECT  41.1 11.13 41.3 304.99 ;
     RECT  40.84 307.93 41.3 324.87 ;
     RECT  41.3 12.53 41.56 304.99 ;
     RECT  41.3 307.93 42.94 323.47 ;
     RECT  41.56 12.53 43.4 303.59 ;
     RECT  42.94 306.53 43.4 323.47 ;
     RECT  43.4 22.015 43.66 303.59 ;
     RECT  43.66 80.675 46.615 80.745 ;
     RECT  43.66 70.595 46.895 70.665 ;
     RECT  43.66 60.515 47.175 60.585 ;
     RECT  43.66 50.435 47.455 50.505 ;
     RECT  43.66 298.235 47.595 299.705 ;
     RECT  43.66 45.395 47.735 45.465 ;
     RECT  48.995 34.895 49.275 34.965 ;
     RECT  48.995 60.795 49.275 60.865 ;
     RECT  49.275 60.795 49.555 63.105 ;
     RECT  49.555 60.795 49.835 65.205 ;
     RECT  47.595 298.095 49.835 299.705 ;
     RECT  49.275 32.795 50.115 34.965 ;
     RECT  49.835 280.035 50.115 280.105 ;
     RECT  49.835 297.395 50.115 299.705 ;
     RECT  50.115 279.895 50.43 280.105 ;
     RECT  50.585 55.825 50.775 55.895 ;
     RECT  50.115 32.095 50.9 34.965 ;
     RECT  50.775 55.825 50.9 57.925 ;
     RECT  49.835 60.795 50.9 67.165 ;
     RECT  50.115 70.035 50.9 70.105 ;
     RECT  50.43 279.895 50.9 280.13 ;
     RECT  50.115 297.255 50.9 299.705 ;
     RECT  50.9 32.095 51.04 37.88 ;
     RECT  50.9 55.825 51.04 70.82 ;
     RECT  50.9 279.825 51.04 280.2 ;
     RECT  50.9 294.97 51.04 299.705 ;
     RECT  43.66 22.015 66.84 25.025 ;
     RECT  66.84 11.13 67.1 25.27 ;
     RECT  51.04 32.095 67.1 299.705 ;
     RECT  67.1 11.13 67.3 304.99 ;
     RECT  66.84 307.93 67.3 324.87 ;
     RECT  67.3 12.53 67.56 304.99 ;
     RECT  67.3 307.93 68.94 323.47 ;
     RECT  67.56 12.53 69.4 303.59 ;
     RECT  68.94 306.53 69.4 323.47 ;
     RECT  69.4 22.015 69.66 303.59 ;
     RECT  69.66 32.095 75.035 299.705 ;
     RECT  69.66 22.015 92.84 25.025 ;
     RECT  92.84 11.13 93.1 25.27 ;
     RECT  75.035 32.095 93.1 299.845 ;
     RECT  93.1 11.13 93.3 304.99 ;
     RECT  92.84 307.93 93.3 324.87 ;
     RECT  93.3 12.53 93.56 304.99 ;
     RECT  93.3 307.93 94.94 323.47 ;
     RECT  93.56 12.53 95.4 303.59 ;
     RECT  94.94 306.53 95.4 323.47 ;
     RECT  95.4 22.015 95.66 303.59 ;
     RECT  95.66 22.015 118.84 25.025 ;
     RECT  118.84 11.13 119.1 25.27 ;
     RECT  95.66 32.095 119.1 299.845 ;
     RECT  119.1 11.13 119.3 304.99 ;
     RECT  118.84 307.93 119.3 324.87 ;
     RECT  119.3 12.53 119.56 304.99 ;
     RECT  119.3 307.93 120.94 323.47 ;
     RECT  119.56 12.53 121.4 303.59 ;
     RECT  120.94 306.53 121.4 323.47 ;
     RECT  121.4 22.015 121.66 303.59 ;
     RECT  121.66 22.015 144.84 25.025 ;
     RECT  144.84 11.13 145.1 25.27 ;
     RECT  121.66 32.095 145.1 299.845 ;
     RECT  145.1 11.13 145.3 304.99 ;
     RECT  144.84 307.93 145.3 324.87 ;
     RECT  145.3 12.53 145.56 304.99 ;
     RECT  145.3 307.93 146.94 323.47 ;
     RECT  145.56 12.53 147.4 303.59 ;
     RECT  146.94 306.53 147.4 323.47 ;
     RECT  147.4 22.015 147.66 303.59 ;
     RECT  147.66 22.015 170.84 25.025 ;
     RECT  170.84 11.13 171.1 25.27 ;
     RECT  147.66 32.095 171.1 299.845 ;
     RECT  171.1 11.13 171.3 304.99 ;
     RECT  170.84 307.93 171.3 324.87 ;
     RECT  171.3 12.53 171.56 304.99 ;
     RECT  171.3 307.93 172.94 323.47 ;
     RECT  171.56 12.53 173.4 303.59 ;
     RECT  172.94 306.53 173.4 323.47 ;
     RECT  173.4 22.015 173.66 303.59 ;
     RECT  173.66 22.015 196.84 25.025 ;
     RECT  196.84 11.13 197.1 25.27 ;
     RECT  173.66 32.095 197.1 299.845 ;
     RECT  197.1 11.13 197.3 304.99 ;
     RECT  196.84 307.93 197.3 324.87 ;
     RECT  197.3 12.53 197.56 304.99 ;
     RECT  197.3 307.93 198.94 323.47 ;
     RECT  197.56 12.53 199.4 303.59 ;
     RECT  198.94 306.53 199.4 323.47 ;
     RECT  199.4 22.015 199.66 303.59 ;
     RECT  199.905 334.635 205.035 334.705 ;
     RECT  205.035 334.495 210.165 334.705 ;
     RECT  210.165 334.355 215.295 334.705 ;
     RECT  199.66 22.015 222.84 25.025 ;
     RECT  222.84 11.13 223.1 25.27 ;
     RECT  199.66 32.095 223.1 299.845 ;
     RECT  223.1 11.13 223.3 304.99 ;
     RECT  222.84 307.93 223.3 324.87 ;
     RECT  223.3 12.53 223.56 304.99 ;
     RECT  223.3 307.93 224.94 323.47 ;
     RECT  223.56 12.53 225.4 303.59 ;
     RECT  224.94 306.53 225.4 323.47 ;
     RECT  225.4 22.015 225.66 303.59 ;
     RECT  215.295 334.075 225.935 334.705 ;
     RECT  225.935 334.075 226.02 334.845 ;
     RECT  226.02 334.075 230.685 334.985 ;
     RECT  230.685 333.935 235.815 334.985 ;
     RECT  235.815 333.795 240.945 334.985 ;
     RECT  240.945 333.655 246.075 334.985 ;
     RECT  225.66 22.015 248.84 25.025 ;
     RECT  248.84 11.13 249.1 25.27 ;
     RECT  225.66 32.095 249.1 299.845 ;
     RECT  249.1 11.13 249.3 304.99 ;
     RECT  248.84 307.93 249.3 324.87 ;
     RECT  249.3 12.53 249.56 304.99 ;
     RECT  249.3 307.93 250.94 323.47 ;
     RECT  249.56 12.53 251.4 303.59 ;
     RECT  250.94 306.53 251.4 323.47 ;
     RECT  251.4 22.015 251.66 303.59 ;
     RECT  251.66 32.095 251.705 299.845 ;
     RECT  251.705 32.095 251.845 37.88 ;
     RECT  251.705 52.22 251.845 52.605 ;
     RECT  251.705 102.79 251.845 117.75 ;
     RECT  251.705 294.97 251.845 299.845 ;
     RECT  251.845 105.875 252.38 112.805 ;
     RECT  246.075 333.515 253.615 334.985 ;
     RECT  253.615 332.955 253.675 334.985 ;
     RECT  251.845 115.955 253.815 117.705 ;
     RECT  253.675 332.815 254.09 334.985 ;
     RECT  252.38 110.915 254.095 112.805 ;
     RECT  254.09 332.815 254.195 334.845 ;
     RECT  251.845 32.095 254.655 35.105 ;
     RECT  251.845 297.255 255.775 299.845 ;
     RECT  252.38 105.875 256.055 107.905 ;
     RECT  251.845 102.795 257.735 102.865 ;
     RECT  251.845 52.255 258.015 52.605 ;
     RECT  255.775 297.255 259.305 297.745 ;
     RECT  258.015 52.535 261.375 52.605 ;
     RECT  254.195 332.815 261.465 334.705 ;
     RECT  259.305 297.255 261.985 299.285 ;
     RECT  261.845 261.975 262.035 262.045 ;
     RECT  261.985 297.255 262.175 299.145 ;
     RECT  257.595 136.115 263.505 136.185 ;
     RECT  261.465 332.815 263.645 334.845 ;
     RECT  262.035 261.695 264.625 262.045 ;
     RECT  254.655 32.095 265.185 34.965 ;
     RECT  265.185 32.095 265.405 35.105 ;
     RECT  253.815 115.955 266.305 116.025 ;
     RECT  266.305 115.955 266.585 117.005 ;
     RECT  263.645 332.815 266.595 334.705 ;
     RECT  251.705 120.995 266.865 121.065 ;
     RECT  260.955 206.675 269.105 206.745 ;
     RECT  266.595 332.815 269.245 334.845 ;
     RECT  269.245 332.815 269.525 334.705 ;
     RECT  251.66 22.015 271.725 25.025 ;
     RECT  269.635 196.595 271.905 196.665 ;
     RECT  254.795 201.635 271.905 201.705 ;
     RECT  269.525 333.375 272.045 334.705 ;
     RECT  263.785 145.215 272.995 145.285 ;
     RECT  254.095 110.915 273.625 110.985 ;
     RECT  272.715 141.155 273.625 141.225 ;
     RECT  271.905 196.595 273.625 201.705 ;
     RECT  272.045 333.375 273.635 334.565 ;
     RECT  256.055 105.875 273.815 105.945 ;
     RECT  251.705 126.035 273.815 126.105 ;
     RECT  260.675 176.435 273.815 176.505 ;
     RECT  264.625 261.415 273.835 262.045 ;
     RECT  251.705 90.755 273.93 90.825 ;
     RECT  272.435 100.835 273.93 100.905 ;
     RECT  273.275 151.235 273.93 151.305 ;
     RECT  251.705 181.475 273.93 181.545 ;
     RECT  255.635 226.835 273.93 226.905 ;
     RECT  255.355 252.035 273.93 252.105 ;
     RECT  266.595 17.115 274.84 17.185 ;
     RECT  271.725 22.015 274.84 25.725 ;
     RECT  265.405 32.095 274.84 34.965 ;
     RECT  265.265 42.595 274.84 42.665 ;
     RECT  274.575 46.795 274.84 46.865 ;
     RECT  266.835 85.715 274.84 85.785 ;
     RECT  273.93 90.755 274.84 91.105 ;
     RECT  260.395 95.795 274.84 95.865 ;
     RECT  273.93 100.835 274.84 101.045 ;
     RECT  273.815 105.875 274.84 106.785 ;
     RECT  273.625 110.915 274.84 111.125 ;
     RECT  266.585 115.955 274.84 117.145 ;
     RECT  266.865 120.995 274.84 122.605 ;
     RECT  273.815 126.035 274.84 126.245 ;
     RECT  255.915 131.075 274.84 131.145 ;
     RECT  263.505 136.115 274.84 136.885 ;
     RECT  273.625 141.155 274.84 142.065 ;
     RECT  272.995 145.215 274.84 146.265 ;
     RECT  273.93 151.235 274.84 151.445 ;
     RECT  273.555 156.275 274.84 156.345 ;
     RECT  273.835 161.315 274.84 161.385 ;
     RECT  261.235 166.355 274.84 166.425 ;
     RECT  257.875 171.395 274.84 171.465 ;
     RECT  273.815 176.435 274.84 176.645 ;
     RECT  273.93 181.475 274.84 182.385 ;
     RECT  258.155 186.515 274.84 186.585 ;
     RECT  254.515 191.555 274.84 191.625 ;
     RECT  273.625 196.595 274.84 201.845 ;
     RECT  269.105 205.135 274.84 206.745 ;
     RECT  255.075 211.715 274.84 211.785 ;
     RECT  258.435 216.755 274.84 216.825 ;
     RECT  255.355 221.795 274.84 221.865 ;
     RECT  273.93 226.835 274.84 227.045 ;
     RECT  255.635 241.955 274.84 242.025 ;
     RECT  258.435 246.995 274.84 247.065 ;
     RECT  273.93 252.035 274.84 252.245 ;
     RECT  261.235 257.075 274.84 257.145 ;
     RECT  273.835 261.415 274.84 262.185 ;
     RECT  262.175 297.255 274.84 297.325 ;
     RECT  271.725 310.555 274.84 310.625 ;
     RECT  251.4 320.775 274.84 320.845 ;
     RECT  274.84 11.13 275.3 324.87 ;
     RECT  275.3 12.53 277.4 323.47 ;
     RECT  277.4 22.015 279.275 25.585 ;
     RECT  277.4 60.375 280.225 60.445 ;
     RECT  277.4 261.975 281.605 262.045 ;
     RECT  277.4 46.795 281.985 46.865 ;
     RECT  277.4 166.355 281.985 166.425 ;
     RECT  281.605 260.995 281.985 262.045 ;
     RECT  281.985 166.355 282.505 167.125 ;
     RECT  281.985 46.375 284.025 46.865 ;
     RECT  284.265 277.935 284.455 278.005 ;
     RECT  277.4 252.175 284.785 252.245 ;
     RECT  277.4 171.395 285.545 171.465 ;
     RECT  277.4 64.995 287.115 65.065 ;
     RECT  284.455 277.795 287.255 278.005 ;
     RECT  287.115 64.995 288.015 65.625 ;
     RECT  282.505 167.055 289.015 167.125 ;
     RECT  281.985 260.995 289.015 262.325 ;
     RECT  289.015 167.055 289.405 167.405 ;
     RECT  273.635 334.495 289.405 334.565 ;
     RECT  284.025 46.795 290.725 46.865 ;
     RECT  290.725 46.795 290.865 48.405 ;
     RECT  287.255 277.795 291.105 277.865 ;
     RECT  277.4 257.075 291.295 257.145 ;
     RECT  289.015 260.995 291.295 262.605 ;
     RECT  291.105 276.955 291.675 277.865 ;
     RECT  287.115 281.995 292.195 282.065 ;
     RECT  291.675 276.955 292.245 279.125 ;
     RECT  292.625 272.195 293.385 272.265 ;
     RECT  292.245 276.955 293.385 279.265 ;
     RECT  291.295 257.075 295.045 262.605 ;
     RECT  277.4 42.595 295.235 42.665 ;
     RECT  293.385 272.195 295.995 279.265 ;
     RECT  289.405 167.055 296.185 167.125 ;
     RECT  277.4 35.735 296.565 35.805 ;
     RECT  295.045 262.115 296.685 262.605 ;
     RECT  295.995 272.195 296.685 279.125 ;
     RECT  296.685 272.195 297.245 272.265 ;
     RECT  296.685 276.535 297.325 279.125 ;
     RECT  295.855 8.575 297.515 8.645 ;
     RECT  297.325 279.055 297.705 279.125 ;
     RECT  284.835 266.595 297.895 266.665 ;
     RECT  297.565 75.075 297.945 75.145 ;
     RECT  279.275 22.155 300.84 25.585 ;
     RECT  290.865 48.335 300.84 48.405 ;
     RECT  298.325 55.335 300.84 55.405 ;
     RECT  288.015 64.995 300.84 65.065 ;
     RECT  297.945 74.935 300.84 75.145 ;
     RECT  277.4 85.715 300.84 85.785 ;
     RECT  277.4 90.755 300.84 90.825 ;
     RECT  277.4 95.795 300.84 95.865 ;
     RECT  277.4 100.975 300.84 101.045 ;
     RECT  277.4 105.875 300.84 105.945 ;
     RECT  277.4 110.915 300.84 110.985 ;
     RECT  277.4 115.955 300.84 116.025 ;
     RECT  277.4 120.995 300.84 121.065 ;
     RECT  277.4 126.175 300.84 126.245 ;
     RECT  277.4 131.075 300.84 131.145 ;
     RECT  277.4 136.115 300.84 136.185 ;
     RECT  277.4 141.155 300.84 141.225 ;
     RECT  277.4 146.195 300.84 146.265 ;
     RECT  277.4 151.375 300.84 151.445 ;
     RECT  277.4 156.275 300.84 156.345 ;
     RECT  277.4 161.315 300.84 161.385 ;
     RECT  296.805 166.915 300.84 166.985 ;
     RECT  294.905 171.395 300.84 171.465 ;
     RECT  277.4 176.575 300.84 176.645 ;
     RECT  277.4 181.475 300.84 181.545 ;
     RECT  277.4 186.515 300.84 186.585 ;
     RECT  277.4 191.555 300.84 191.625 ;
     RECT  277.4 196.595 300.84 196.665 ;
     RECT  277.4 201.775 300.84 201.845 ;
     RECT  277.4 206.675 300.84 206.745 ;
     RECT  277.4 211.715 300.84 211.785 ;
     RECT  277.4 216.755 300.84 216.825 ;
     RECT  277.4 221.795 300.84 221.865 ;
     RECT  277.4 226.975 300.84 227.045 ;
     RECT  277.4 241.955 300.84 242.025 ;
     RECT  277.4 246.995 300.84 247.065 ;
     RECT  295.665 252.175 300.84 252.245 ;
     RECT  295.045 257.075 300.84 257.145 ;
     RECT  296.685 262.115 300.84 262.185 ;
     RECT  300.84 11.13 301.3 324.87 ;
     RECT  299.845 0.175 301.935 0.245 ;
     RECT  301.935 0.175 302.645 2.905 ;
     RECT  301.3 12.53 303.4 323.47 ;
     RECT  303.4 42.735 303.785 42.805 ;
     RECT  303.4 190.995 303.965 192.465 ;
     RECT  303.4 126.035 304.07 126.245 ;
     RECT  303.4 166.355 304.07 166.985 ;
     RECT  303.4 176.435 304.07 176.645 ;
     RECT  303.4 201.635 304.07 201.845 ;
     RECT  303.4 85.715 304.165 85.925 ;
     RECT  303.4 156.275 304.165 156.485 ;
     RECT  303.4 161.315 304.165 161.665 ;
     RECT  303.965 191.555 304.165 192.465 ;
     RECT  303.4 257.075 304.165 262.185 ;
     RECT  303.4 54.075 304.355 54.145 ;
     RECT  303.4 216.755 304.355 217.525 ;
     RECT  304.165 156.275 304.445 156.345 ;
     RECT  303.4 151.235 304.725 151.445 ;
     RECT  303.4 146.195 305.005 146.265 ;
     RECT  304.725 151.375 305.115 151.445 ;
     RECT  303.4 141.155 305.285 141.225 ;
     RECT  303.4 100.835 305.565 102.725 ;
     RECT  296.545 333.235 306.065 333.305 ;
     RECT  303.4 196.595 306.205 196.945 ;
     RECT  303.4 206.675 306.485 208.145 ;
     RECT  304.165 161.595 307.325 161.665 ;
     RECT  306.065 333.235 307.465 334.145 ;
     RECT  303.4 211.715 307.605 213.885 ;
     RECT  302.645 2.835 307.775 2.905 ;
     RECT  307.465 333.235 307.775 334.845 ;
     RECT  306.205 196.595 308.365 196.805 ;
     RECT  308.365 196.735 309.285 196.805 ;
     RECT  307.775 333.235 309.425 334.565 ;
     RECT  303.4 226.835 309.565 228.165 ;
     RECT  303.4 241.955 309.845 242.165 ;
     RECT  303.4 252.035 310.125 253.785 ;
     RECT  304.165 85.715 311.165 85.785 ;
     RECT  303.4 90.755 312.085 91.245 ;
     RECT  303.4 95.795 312.365 96.985 ;
     RECT  305.565 102.655 312.645 102.725 ;
     RECT  309.425 332.955 312.785 334.565 ;
     RECT  312.765 0.175 312.925 0.245 ;
     RECT  303.4 51.135 312.925 51.205 ;
     RECT  303.4 115.955 312.925 117.005 ;
     RECT  303.4 136.115 314.885 137.025 ;
     RECT  303.4 297.255 316.375 297.325 ;
     RECT  304.165 257.075 316.515 259.525 ;
     RECT  304.07 166.355 316.765 166.425 ;
     RECT  316.515 257.075 316.765 257.145 ;
     RECT  306.485 206.675 317.045 206.745 ;
     RECT  304.07 176.435 317.325 176.505 ;
     RECT  312.365 95.795 317.605 95.865 ;
     RECT  312.785 332.955 318.035 334.845 ;
     RECT  316.375 297.255 319.085 298.025 ;
     RECT  304.355 216.755 319.565 216.825 ;
     RECT  303.4 246.995 319.565 247.065 ;
     RECT  303.4 186.515 319.845 186.585 ;
     RECT  316.625 52.535 319.985 52.605 ;
     RECT  303.4 171.395 320.125 171.465 ;
     RECT  314.885 136.115 320.405 136.185 ;
     RECT  303.4 105.875 321.945 105.945 ;
     RECT  303.4 131.075 322.085 131.145 ;
     RECT  319.085 297.255 322.225 297.745 ;
     RECT  309.565 226.835 322.365 226.905 ;
     RECT  309.845 241.955 322.365 242.025 ;
     RECT  303.4 221.795 322.645 221.865 ;
     RECT  310.125 252.035 322.645 252.105 ;
     RECT  307.605 211.715 322.925 211.785 ;
     RECT  304.07 201.635 323.205 201.705 ;
     RECT  303.4 32.095 323.345 34.965 ;
     RECT  304.165 191.555 323.485 191.625 ;
     RECT  303.4 110.915 323.905 110.985 ;
     RECT  312.925 115.955 324.185 116.025 ;
     RECT  321.945 105.875 325.62 107.905 ;
     RECT  323.905 110.915 325.62 112.805 ;
     RECT  323.345 32.095 326.155 35.105 ;
     RECT  319.985 52.255 326.155 52.605 ;
     RECT  320.265 102.795 326.155 102.865 ;
     RECT  325.62 105.875 326.155 112.805 ;
     RECT  324.185 115.955 326.155 117.705 ;
     RECT  322.225 297.255 326.155 299.845 ;
     RECT  326.155 32.095 326.295 37.88 ;
     RECT  326.155 52.22 326.295 52.605 ;
     RECT  312.085 90.755 326.295 90.825 ;
     RECT  326.155 102.79 326.295 117.75 ;
     RECT  303.4 120.995 326.295 121.065 ;
     RECT  304.07 126.035 326.295 126.105 ;
     RECT  303.4 181.475 326.295 181.545 ;
     RECT  326.155 294.97 326.295 299.845 ;
     RECT  303.4 23.975 326.34 25.585 ;
     RECT  326.295 32.095 326.34 299.845 ;
     RECT  326.34 23.975 326.84 303.59 ;
     RECT  307.185 309.155 326.84 309.225 ;
     RECT  309.705 326.235 326.84 326.305 ;
     RECT  326.84 11.13 327.3 303.59 ;
     RECT  326.84 307.93 328.295 326.305 ;
     RECT  327.3 12.53 328.44 303.59 ;
     RECT  328.44 12.53 328.9 304.99 ;
     RECT  328.295 307.93 328.94 323.47 ;
     RECT  328.9 12.53 329.4 25.585 ;
     RECT  328.94 306.53 329.4 323.47 ;
     RECT  329.4 309.155 348.815 309.225 ;
     RECT  329.4 23.975 352.34 25.585 ;
     RECT  328.9 32.095 352.34 299.845 ;
     RECT  352.34 23.975 352.84 303.59 ;
     RECT  352.84 11.13 353.3 303.59 ;
     RECT  352.84 307.93 353.3 324.87 ;
     RECT  353.3 12.53 354.44 303.59 ;
     RECT  354.44 12.53 354.9 304.99 ;
     RECT  353.3 307.93 354.94 323.47 ;
     RECT  354.9 12.53 355.4 25.585 ;
     RECT  354.94 306.53 355.4 323.47 ;
     RECT  318.035 332.955 374.465 334.565 ;
     RECT  355.4 23.975 378.34 25.585 ;
     RECT  354.9 32.095 378.34 299.845 ;
     RECT  378.34 23.975 378.84 303.59 ;
     RECT  378.84 11.13 379.3 303.59 ;
     RECT  378.84 307.93 379.3 324.87 ;
     RECT  374.465 332.955 379.595 333.025 ;
     RECT  379.3 12.53 380.44 303.59 ;
     RECT  380.44 12.53 380.9 304.99 ;
     RECT  379.3 307.93 380.94 323.47 ;
     RECT  380.9 12.53 381.4 25.585 ;
     RECT  380.94 306.53 381.4 323.47 ;
     RECT  381.4 23.975 404.34 25.585 ;
     RECT  380.9 32.095 404.34 299.845 ;
     RECT  404.34 23.975 404.84 303.59 ;
     RECT  404.84 11.13 405.3 303.59 ;
     RECT  404.84 307.93 405.3 324.87 ;
     RECT  405.3 12.53 406.44 303.59 ;
     RECT  406.44 12.53 406.9 304.99 ;
     RECT  405.3 307.93 406.94 323.47 ;
     RECT  406.9 12.53 407.4 25.585 ;
     RECT  406.94 306.53 407.4 323.47 ;
     RECT  407.4 23.975 430.34 25.585 ;
     RECT  406.9 32.095 430.34 299.845 ;
     RECT  430.34 23.975 430.84 303.59 ;
     RECT  430.84 11.13 431.3 303.59 ;
     RECT  430.84 307.93 431.3 324.87 ;
     RECT  431.3 12.53 432.44 303.59 ;
     RECT  432.44 12.53 432.9 304.99 ;
     RECT  431.3 307.93 432.94 323.47 ;
     RECT  432.9 12.53 433.4 25.585 ;
     RECT  432.94 306.53 433.4 323.47 ;
     RECT  433.4 23.975 456.34 25.585 ;
     RECT  432.9 32.095 456.34 299.845 ;
     RECT  456.34 23.975 456.84 303.59 ;
     RECT  456.84 11.13 457.3 303.59 ;
     RECT  456.84 307.93 457.3 324.87 ;
     RECT  457.3 12.53 458.44 303.59 ;
     RECT  458.44 12.53 458.9 304.99 ;
     RECT  457.3 307.93 458.94 323.47 ;
     RECT  458.9 12.53 459.4 25.585 ;
     RECT  458.94 306.53 459.4 323.47 ;
     RECT  459.4 23.975 482.34 25.585 ;
     RECT  458.9 32.095 482.34 299.845 ;
     RECT  482.34 23.975 482.84 303.59 ;
     RECT  482.84 11.13 483.3 303.59 ;
     RECT  482.84 307.93 483.3 324.87 ;
     RECT  483.3 12.53 484.44 303.59 ;
     RECT  484.44 12.53 484.9 304.99 ;
     RECT  483.3 307.93 484.94 323.47 ;
     RECT  484.9 12.53 485.4 25.585 ;
     RECT  484.94 306.53 485.4 323.47 ;
     RECT  484.9 32.095 502.965 299.845 ;
     RECT  485.4 23.975 508.34 25.585 ;
     RECT  502.965 32.095 508.34 299.705 ;
     RECT  508.34 23.975 508.84 303.59 ;
     RECT  508.84 11.13 509.3 303.59 ;
     RECT  508.84 307.93 509.3 324.87 ;
     RECT  509.3 12.53 510.44 303.59 ;
     RECT  510.44 12.53 510.9 304.99 ;
     RECT  509.3 307.93 510.94 323.47 ;
     RECT  510.9 12.53 511.4 25.585 ;
     RECT  510.94 306.53 511.4 323.47 ;
     RECT  510.9 32.095 526.96 299.705 ;
     RECT  526.96 32.095 527.1 37.88 ;
     RECT  526.96 55.825 527.1 70.82 ;
     RECT  526.96 279.825 527.1 280.2 ;
     RECT  526.96 294.97 527.1 299.705 ;
     RECT  527.1 55.825 527.225 57.925 ;
     RECT  527.225 55.825 527.415 55.895 ;
     RECT  527.1 279.895 527.57 280.13 ;
     RECT  527.1 32.095 527.885 34.965 ;
     RECT  527.1 70.035 527.885 70.105 ;
     RECT  527.57 279.895 527.885 280.105 ;
     RECT  527.1 297.255 527.885 299.705 ;
     RECT  527.1 60.795 528.165 67.165 ;
     RECT  527.885 280.035 528.165 280.105 ;
     RECT  527.885 297.395 528.165 299.705 ;
     RECT  528.165 60.795 528.445 65.205 ;
     RECT  527.885 32.795 528.725 34.965 ;
     RECT  528.445 60.795 528.725 63.105 ;
     RECT  528.725 34.895 529.005 34.965 ;
     RECT  528.725 60.795 529.005 60.865 ;
     RECT  528.165 298.095 530.405 299.705 ;
     RECT  511.4 23.975 534.34 25.585 ;
     RECT  530.265 45.395 534.34 45.465 ;
     RECT  530.545 50.435 534.34 50.505 ;
     RECT  530.825 60.515 534.34 60.585 ;
     RECT  531.105 70.595 534.34 70.665 ;
     RECT  531.385 80.675 534.34 80.745 ;
     RECT  530.405 298.235 534.34 299.705 ;
     RECT  534.34 23.975 534.84 303.59 ;
     RECT  534.84 11.13 535.3 303.59 ;
     RECT  534.84 307.93 535.3 324.87 ;
     RECT  535.3 12.53 536.44 303.59 ;
     RECT  536.44 12.53 536.9 304.99 ;
     RECT  535.3 307.93 536.94 323.47 ;
     RECT  536.9 12.53 537.4 25.585 ;
     RECT  536.94 306.53 537.4 323.47 ;
     RECT  536.9 298.235 539.365 299.705 ;
     RECT  536.9 60.515 539.865 60.585 ;
     RECT  539.365 298.235 542.165 299.565 ;
     RECT  541.745 65.555 542.665 65.625 ;
     RECT  536.9 90.755 545.465 90.825 ;
     RECT  542.025 85.715 545.745 85.785 ;
     RECT  536.9 80.675 546.025 80.745 ;
     RECT  537.4 23.975 546.165 25.585 ;
     RECT  546.165 24.115 546.445 25.585 ;
     RECT  536.9 70.595 546.585 70.665 ;
     RECT  536.9 75.635 547.145 75.705 ;
     RECT  536.9 45.395 547.225 45.465 ;
     RECT  546.445 24.115 547.285 24.745 ;
     RECT  547.285 24.535 547.365 24.745 ;
     RECT  536.9 50.435 547.425 50.505 ;
     RECT  547.365 24.535 547.565 24.605 ;
     RECT  547.145 55.335 548.745 55.405 ;
     RECT  542.165 299.495 548.885 299.565 ;
     RECT  547.225 45.255 549 45.465 ;
     RECT  547.425 50.295 549 50.505 ;
     RECT  548.745 55.335 549 55.545 ;
     RECT  539.865 60.375 549 60.585 ;
     RECT  542.665 65.555 549 65.765 ;
     RECT  546.585 70.455 549 70.665 ;
     RECT  547.145 75.495 549 75.705 ;
     RECT  546.025 80.535 549 80.745 ;
     RECT  545.745 85.575 549 85.785 ;
     RECT  545.465 90.615 549 90.825 ;
     RECT  560.84 11.13 561.3 324.87 ;
     RECT  561.3 12.53 563.4 323.47 ;
    LAYER metal4 ;
     RECT  14.82 11.13 15.32 11.16 ;
     RECT  40.82 11.13 41.32 11.16 ;
     RECT  66.82 11.13 67.32 11.16 ;
     RECT  92.82 11.13 93.32 11.16 ;
     RECT  118.82 11.13 119.32 11.16 ;
     RECT  144.82 11.13 145.32 11.16 ;
     RECT  170.82 11.13 171.32 11.16 ;
     RECT  196.82 11.13 197.32 11.16 ;
     RECT  222.82 11.13 223.32 11.16 ;
     RECT  248.82 11.13 249.32 11.16 ;
     RECT  274.82 11.13 275.32 11.16 ;
     RECT  300.82 11.13 301.32 11.16 ;
     RECT  326.82 11.13 327.32 11.16 ;
     RECT  352.82 11.13 353.32 11.16 ;
     RECT  378.82 11.13 379.32 11.16 ;
     RECT  404.82 11.13 405.32 11.16 ;
     RECT  430.82 11.13 431.32 11.16 ;
     RECT  456.82 11.13 457.32 11.16 ;
     RECT  482.82 11.13 483.32 11.16 ;
     RECT  508.82 11.13 509.32 11.16 ;
     RECT  534.82 11.13 535.32 11.16 ;
     RECT  560.82 11.13 561.32 11.16 ;
     RECT  33.065 22.12 33.205 22.54 ;
     RECT  546.025 23.94 546.165 24.08 ;
     RECT  32.505 22.54 33.205 24.22 ;
     RECT  40.82 11.16 43.42 24.22 ;
     RECT  546.025 24.08 547.285 24.22 ;
     RECT  32.505 24.22 43.42 24.5 ;
     RECT  545.465 24.22 547.285 24.5 ;
     RECT  534.82 11.16 537.42 24.78 ;
     RECT  545.465 24.5 547.565 24.78 ;
     RECT  66.82 11.16 69.42 25.74 ;
     RECT  92.82 11.16 95.42 25.74 ;
     RECT  118.82 11.16 121.42 25.74 ;
     RECT  144.82 11.16 147.42 25.74 ;
     RECT  170.82 11.16 173.42 25.74 ;
     RECT  196.82 11.16 199.42 25.74 ;
     RECT  222.82 11.16 225.42 25.74 ;
     RECT  248.82 11.16 251.42 25.74 ;
     RECT  326.82 11.16 329.42 25.74 ;
     RECT  352.82 11.16 355.42 25.74 ;
     RECT  378.82 11.16 381.42 25.74 ;
     RECT  404.82 11.16 407.42 25.74 ;
     RECT  430.82 11.16 433.42 25.74 ;
     RECT  456.82 11.16 459.42 25.74 ;
     RECT  482.82 11.16 485.42 25.74 ;
     RECT  508.82 11.16 511.42 25.74 ;
     RECT  29.425 24.5 43.42 26.07 ;
     RECT  67.08 25.74 69.42 26.07 ;
     RECT  93.08 25.74 95.42 26.07 ;
     RECT  119.08 25.74 121.42 26.07 ;
     RECT  145.08 25.74 147.42 26.07 ;
     RECT  171.08 25.74 173.42 26.07 ;
     RECT  197.08 25.74 199.42 26.07 ;
     RECT  223.08 25.74 225.42 26.07 ;
     RECT  249.08 25.74 251.42 26.07 ;
     RECT  326.82 25.74 328.92 26.07 ;
     RECT  352.82 25.74 354.92 26.07 ;
     RECT  378.82 25.74 380.92 26.07 ;
     RECT  404.82 25.74 406.92 26.07 ;
     RECT  430.82 25.74 432.92 26.07 ;
     RECT  456.82 25.74 458.92 26.07 ;
     RECT  482.82 25.74 484.92 26.07 ;
     RECT  508.82 25.74 510.92 26.07 ;
     RECT  534.82 24.78 547.565 26.07 ;
     RECT  274.82 11.16 277.42 32.06 ;
     RECT  300.82 11.16 303.42 32.06 ;
     RECT  223.08 26.07 225.68 32.34 ;
     RECT  249.08 26.07 251.68 32.34 ;
     RECT  258.155 32.2 258.295 32.34 ;
     RECT  319.705 32.2 319.845 32.34 ;
     RECT  326.32 26.07 328.92 32.34 ;
     RECT  352.32 26.07 354.92 32.34 ;
     RECT  216.155 32.2 216.295 32.48 ;
     RECT  223.08 32.34 230.575 32.48 ;
     RECT  347.425 32.34 354.92 32.48 ;
     RECT  361.705 32.2 361.845 32.48 ;
     RECT  249.08 32.34 258.295 32.62 ;
     RECT  265.185 24.5 265.325 32.62 ;
     RECT  312.785 0.14 312.925 32.62 ;
     RECT  319.705 32.34 328.92 32.62 ;
     RECT  29.425 26.07 43.68 32.76 ;
     RECT  50.115 32.06 50.255 32.76 ;
     RECT  527.745 32.06 527.885 32.76 ;
     RECT  534.32 26.07 547.565 32.76 ;
     RECT  197.08 26.07 199.68 32.9 ;
     RECT  378.32 26.07 380.92 32.9 ;
     RECT  197.08 32.9 202.015 33.46 ;
     RECT  375.985 32.9 380.92 33.46 ;
     RECT  197.08 33.46 207.615 33.74 ;
     RECT  370.385 33.46 380.92 33.74 ;
     RECT  196.275 33.74 207.615 34.02 ;
     RECT  216.155 32.48 230.575 34.02 ;
     RECT  249.08 32.62 265.325 34.02 ;
     RECT  272.435 32.06 277.42 34.02 ;
     RECT  300.82 32.06 305.565 34.02 ;
     RECT  312.785 32.62 328.92 34.02 ;
     RECT  347.425 32.48 361.845 34.02 ;
     RECT  370.385 33.74 381.725 34.02 ;
     RECT  249.08 34.02 277.42 35.14 ;
     RECT  196.275 34.02 230.575 35.84 ;
     RECT  347.425 34.02 381.725 35.84 ;
     RECT  29.425 32.76 50.255 37.18 ;
     RECT  527.745 32.76 547.565 37.18 ;
     RECT  29.425 37.18 51.6 37.32 ;
     RECT  67.08 26.07 69.68 37.32 ;
     RECT  93.08 26.07 95.68 37.32 ;
     RECT  119.08 26.07 121.68 37.32 ;
     RECT  145.08 26.07 147.68 37.32 ;
     RECT  171.08 26.07 173.68 37.32 ;
     RECT  196.115 35.84 230.575 37.32 ;
     RECT  249.08 35.14 261.095 37.32 ;
     RECT  300.82 34.02 328.92 37.32 ;
     RECT  347.425 35.84 381.885 37.32 ;
     RECT  404.32 26.07 406.92 37.32 ;
     RECT  430.32 26.07 432.92 37.32 ;
     RECT  456.32 26.07 458.92 37.32 ;
     RECT  482.32 26.07 484.92 37.32 ;
     RECT  508.32 26.07 510.92 37.32 ;
     RECT  526.4 37.18 547.565 37.32 ;
     RECT  29.425 37.32 261.095 52.5 ;
     RECT  266.835 35.14 277.42 52.5 ;
     RECT  29.425 52.5 277.42 55.44 ;
     RECT  300.82 37.32 547.565 55.44 ;
     RECT  29.115 55.44 277.42 85.82 ;
     RECT  29.115 85.82 261.375 90.72 ;
     RECT  300.82 55.44 548.885 90.72 ;
     RECT  35.835 90.72 261.375 116.9 ;
     RECT  269.635 85.82 277.42 116.9 ;
     RECT  35.835 116.9 277.42 216.86 ;
     RECT  300.82 90.72 542.165 216.86 ;
     RECT  35.835 216.86 255.775 226.94 ;
     RECT  322.225 216.86 542.165 226.94 ;
     RECT  35.835 226.94 251.845 241.92 ;
     RECT  326.155 226.94 542.165 241.92 ;
     RECT  35.835 241.92 255.775 246.96 ;
     RECT  263.505 216.86 277.42 246.96 ;
     RECT  300.82 216.86 314.885 246.96 ;
     RECT  322.225 241.92 542.165 246.96 ;
     RECT  300.82 246.96 542.165 262.5 ;
     RECT  35.835 246.96 277.42 295.53 ;
     RECT  296.545 262.5 542.165 295.53 ;
     RECT  35.835 295.53 51.6 295.67 ;
     RECT  526.4 295.53 542.165 295.67 ;
     RECT  104.995 295.53 105.255 296.1 ;
     RECT  142.715 295.53 152.255 296.1 ;
     RECT  181.435 295.53 181.715 296.1 ;
     RECT  396.285 295.53 396.565 296.1 ;
     RECT  425.745 295.53 435.285 296.1 ;
     RECT  472.745 295.53 473.005 296.1 ;
     RECT  114.515 295.53 124.055 296.94 ;
     RECT  133.275 295.53 133.455 296.94 ;
     RECT  142.715 296.1 152.175 296.94 ;
     RECT  190.955 295.53 191.115 296.94 ;
     RECT  197.08 295.53 200.515 296.94 ;
     RECT  209.715 295.53 209.915 296.94 ;
     RECT  368.085 295.53 368.285 296.94 ;
     RECT  377.485 295.53 380.92 296.94 ;
     RECT  386.885 295.53 387.045 296.94 ;
     RECT  425.825 296.1 435.285 296.94 ;
     RECT  444.545 295.53 444.725 296.94 ;
     RECT  453.945 295.53 463.485 296.94 ;
     RECT  35.835 295.67 50.255 297.36 ;
     RECT  527.745 295.67 542.165 297.36 ;
     RECT  35.835 297.36 49.975 297.5 ;
     RECT  528.025 297.36 542.165 297.5 ;
     RECT  67.08 295.53 81.055 297.64 ;
     RECT  496.945 295.53 510.92 297.64 ;
     RECT  80.915 297.64 81.055 297.78 ;
     RECT  496.945 297.64 497.085 297.78 ;
     RECT  35.835 297.5 47.735 298.2 ;
     RECT  209.715 296.94 209.855 298.2 ;
     RECT  368.145 296.94 368.285 298.2 ;
     RECT  530.265 297.5 542.165 298.2 ;
     RECT  35.835 298.2 47.455 298.34 ;
     RECT  190.955 296.94 191.095 298.34 ;
     RECT  386.905 296.94 387.045 298.34 ;
     RECT  530.545 298.2 542.165 298.34 ;
     RECT  181.435 296.1 181.575 298.48 ;
     RECT  396.425 296.1 396.565 298.48 ;
     RECT  142.795 296.94 152.175 298.62 ;
     RECT  425.825 296.94 435.205 298.62 ;
     RECT  36.115 298.34 47.455 298.76 ;
     RECT  133.275 296.94 133.415 298.76 ;
     RECT  444.585 296.94 444.725 298.76 ;
     RECT  530.545 298.34 541.885 298.76 ;
     RECT  142.795 298.62 147.68 298.9 ;
     RECT  430.32 298.62 435.205 298.9 ;
     RECT  38.635 298.76 47.455 299.04 ;
     RECT  104.995 296.1 105.135 299.04 ;
     RECT  472.865 296.1 473.005 299.04 ;
     RECT  530.545 298.76 539.365 299.04 ;
     RECT  38.635 299.04 47.175 299.18 ;
     RECT  114.515 296.94 123.895 299.18 ;
     RECT  454.105 296.94 463.485 299.18 ;
     RECT  530.825 299.04 539.365 299.18 ;
     RECT  29.115 90.72 29.255 299.6 ;
     RECT  114.515 299.18 121.68 299.6 ;
     RECT  456.32 299.18 463.485 299.6 ;
     RECT  548.745 90.72 548.885 299.6 ;
     RECT  38.635 299.18 43.68 299.74 ;
     RECT  197.08 296.94 200.335 299.74 ;
     RECT  377.665 296.94 380.92 299.74 ;
     RECT  534.32 299.18 539.365 299.74 ;
     RECT  67.08 297.64 75.175 299.88 ;
     RECT  249.08 295.53 277.42 299.88 ;
     RECT  296.545 295.53 328.92 299.88 ;
     RECT  502.825 297.64 510.92 299.88 ;
     RECT  41.08 299.74 43.68 304.96 ;
     RECT  67.08 299.88 69.68 304.96 ;
     RECT  93.08 295.53 95.68 304.96 ;
     RECT  119.08 299.6 121.68 304.96 ;
     RECT  145.08 298.9 147.68 304.96 ;
     RECT  171.08 295.53 173.68 304.96 ;
     RECT  197.08 299.74 199.68 304.96 ;
     RECT  223.08 295.53 225.68 304.96 ;
     RECT  249.08 299.88 251.68 304.96 ;
     RECT  326.32 299.88 328.92 304.96 ;
     RECT  352.32 295.53 354.92 304.96 ;
     RECT  378.32 299.74 380.92 304.96 ;
     RECT  404.32 295.53 406.92 304.96 ;
     RECT  430.32 298.9 432.92 304.96 ;
     RECT  456.32 299.6 458.92 304.96 ;
     RECT  482.32 295.53 484.92 304.96 ;
     RECT  508.32 299.88 510.92 304.96 ;
     RECT  534.32 299.74 536.92 304.96 ;
     RECT  41.08 304.96 43.42 305.53 ;
     RECT  67.08 304.96 69.42 305.53 ;
     RECT  93.08 304.96 95.42 305.53 ;
     RECT  119.08 304.96 121.42 305.53 ;
     RECT  145.08 304.96 147.42 305.53 ;
     RECT  171.08 304.96 173.42 305.53 ;
     RECT  197.08 304.96 199.42 305.53 ;
     RECT  223.08 304.96 225.42 305.53 ;
     RECT  249.08 304.96 251.42 305.53 ;
     RECT  326.82 304.96 328.92 305.53 ;
     RECT  352.82 304.96 354.92 305.53 ;
     RECT  378.82 304.96 380.92 305.53 ;
     RECT  404.82 304.96 406.92 305.53 ;
     RECT  430.82 304.96 432.92 305.53 ;
     RECT  456.82 304.96 458.92 305.53 ;
     RECT  482.82 304.96 484.92 305.53 ;
     RECT  508.82 304.96 510.92 305.53 ;
     RECT  534.82 304.96 536.92 305.53 ;
     RECT  14.82 11.16 17.42 324.84 ;
     RECT  40.82 305.53 43.42 324.84 ;
     RECT  66.82 305.53 69.42 324.84 ;
     RECT  92.82 305.53 95.42 324.84 ;
     RECT  118.82 305.53 121.42 324.84 ;
     RECT  144.82 305.53 147.42 324.84 ;
     RECT  170.82 305.53 173.42 324.84 ;
     RECT  196.82 305.53 199.42 324.84 ;
     RECT  222.82 305.53 225.42 324.84 ;
     RECT  248.82 305.53 251.42 324.84 ;
     RECT  259.305 299.88 277.42 324.84 ;
     RECT  326.82 305.53 329.42 324.84 ;
     RECT  352.82 305.53 355.42 324.84 ;
     RECT  378.82 305.53 381.42 324.84 ;
     RECT  404.82 305.53 407.42 324.84 ;
     RECT  430.82 305.53 433.42 324.84 ;
     RECT  456.82 305.53 459.42 324.84 ;
     RECT  482.82 305.53 485.42 324.84 ;
     RECT  508.82 305.53 511.42 324.84 ;
     RECT  534.82 305.53 537.42 324.84 ;
     RECT  560.82 11.16 563.42 324.84 ;
     RECT  14.82 324.84 15.32 324.87 ;
     RECT  40.82 324.84 41.32 324.87 ;
     RECT  66.82 324.84 67.32 324.87 ;
     RECT  92.82 324.84 93.32 324.87 ;
     RECT  118.82 324.84 119.32 324.87 ;
     RECT  144.82 324.84 145.32 324.87 ;
     RECT  170.82 324.84 171.32 324.87 ;
     RECT  196.82 324.84 197.32 324.87 ;
     RECT  222.82 324.84 223.32 324.87 ;
     RECT  248.82 324.84 249.32 324.87 ;
     RECT  259.305 324.84 275.32 324.87 ;
     RECT  296.545 299.88 319.085 324.87 ;
     RECT  326.82 324.84 327.32 324.87 ;
     RECT  352.82 324.84 353.32 324.87 ;
     RECT  378.82 324.84 379.32 324.87 ;
     RECT  404.82 324.84 405.32 324.87 ;
     RECT  430.82 324.84 431.32 324.87 ;
     RECT  456.82 324.84 457.32 324.87 ;
     RECT  482.82 324.84 483.32 324.87 ;
     RECT  508.82 324.84 509.32 324.87 ;
     RECT  534.82 324.84 535.32 324.87 ;
     RECT  560.82 324.84 561.32 324.87 ;
     RECT  296.545 324.87 296.685 333.34 ;
     RECT  306.065 324.87 319.085 333.62 ;
     RECT  306.065 333.62 314.885 334.18 ;
     RECT  259.305 324.87 272.045 334.46 ;
     RECT  289.265 167.3 289.405 334.6 ;
     RECT  307.465 334.18 314.885 334.6 ;
     RECT  263.505 334.46 272.045 334.74 ;
     RECT  263.505 334.74 269.245 334.88 ;
     RECT  307.465 334.6 312.925 334.88 ;
    LAYER metal5 ;
     RECT  10.07 285.95 38.62 288.55 ;
     RECT  10.07 45.95 39.16 48.55 ;
     RECT  10.07 75.95 39.16 78.55 ;
     RECT  10.07 105.95 39.16 108.55 ;
     RECT  10.07 135.95 39.16 138.55 ;
     RECT  10.07 225.95 39.16 228.55 ;
     RECT  10.07 255.95 39.16 258.55 ;
     RECT  38.62 286.07 39.16 288.55 ;
     RECT  224.715 37.18 224.835 37.32 ;
     RECT  224.835 36.96 224.975 37.32 ;
     RECT  224.975 36.96 227.575 37.1 ;
     RECT  227.575 36.68 260.535 37.1 ;
     RECT  39.16 26.07 263.93 28.67 ;
     RECT  39.16 45.95 263.93 54.67 ;
     RECT  39.16 75.95 263.93 80.67 ;
     RECT  39.16 104.07 263.93 108.55 ;
     RECT  39.16 130.07 263.93 138.55 ;
     RECT  39.16 156.07 263.93 158.67 ;
     RECT  39.16 182.07 263.93 184.67 ;
     RECT  39.16 208.07 263.93 210.67 ;
     RECT  39.16 225.95 263.93 236.67 ;
     RECT  39.16 255.95 263.93 262.67 ;
     RECT  39.16 286.07 263.93 288.67 ;
     RECT  41.08 299.14 263.93 301.88 ;
     RECT  263.93 286.07 264.47 288.55 ;
     RECT  260.535 36.68 266.975 36.82 ;
     RECT  264.47 285.95 313.53 288.55 ;
     RECT  263.93 45.95 314.07 48.55 ;
     RECT  263.93 75.95 314.07 78.55 ;
     RECT  263.93 105.95 314.07 108.55 ;
     RECT  263.93 135.95 314.07 138.55 ;
     RECT  263.93 225.95 314.07 228.55 ;
     RECT  263.93 255.95 314.07 258.55 ;
     RECT  313.53 286.07 314.07 288.55 ;
     RECT  311.025 36.68 317.465 36.82 ;
     RECT  317.465 36.68 350.425 37.1 ;
     RECT  350.425 36.96 353.025 37.1 ;
     RECT  353.025 36.96 353.165 37.32 ;
     RECT  353.165 37.18 353.285 37.32 ;
     RECT  314.07 299.14 536.92 301.88 ;
     RECT  314.07 26.07 538.84 28.67 ;
     RECT  314.07 45.95 538.84 54.67 ;
     RECT  314.07 75.95 538.84 80.67 ;
     RECT  314.07 104.07 538.84 108.55 ;
     RECT  314.07 130.07 538.84 138.55 ;
     RECT  314.07 156.07 538.84 158.67 ;
     RECT  314.07 182.07 538.84 184.67 ;
     RECT  314.07 208.07 538.84 210.67 ;
     RECT  314.07 225.95 538.84 236.67 ;
     RECT  314.07 255.95 538.84 262.67 ;
     RECT  314.07 286.07 538.84 288.67 ;
     RECT  538.84 286.07 539.38 288.55 ;
     RECT  10.07 15.95 570 18.55 ;
     RECT  538.84 45.95 570 48.55 ;
     RECT  538.84 75.95 570 78.55 ;
     RECT  538.84 105.95 570 108.55 ;
     RECT  538.84 135.95 570 138.55 ;
     RECT  10.07 165.95 570 168.55 ;
     RECT  10.07 195.95 570 198.55 ;
     RECT  538.84 225.95 570 228.55 ;
     RECT  538.84 255.95 570 258.55 ;
     RECT  539.38 285.95 570 288.55 ;
     RECT  10.07 315.95 570 318.55 ;
  END
END SRAM10x2048
END LIBRARY
